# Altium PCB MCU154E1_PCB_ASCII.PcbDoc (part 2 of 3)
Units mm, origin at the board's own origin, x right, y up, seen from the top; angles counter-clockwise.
Board outline 105 x 85 mm, 2 copper layers (Top Layer, Bottom Layer), stack 1.6 mm thick; 179 components, 92 nets, 411 pads, 187 vias.

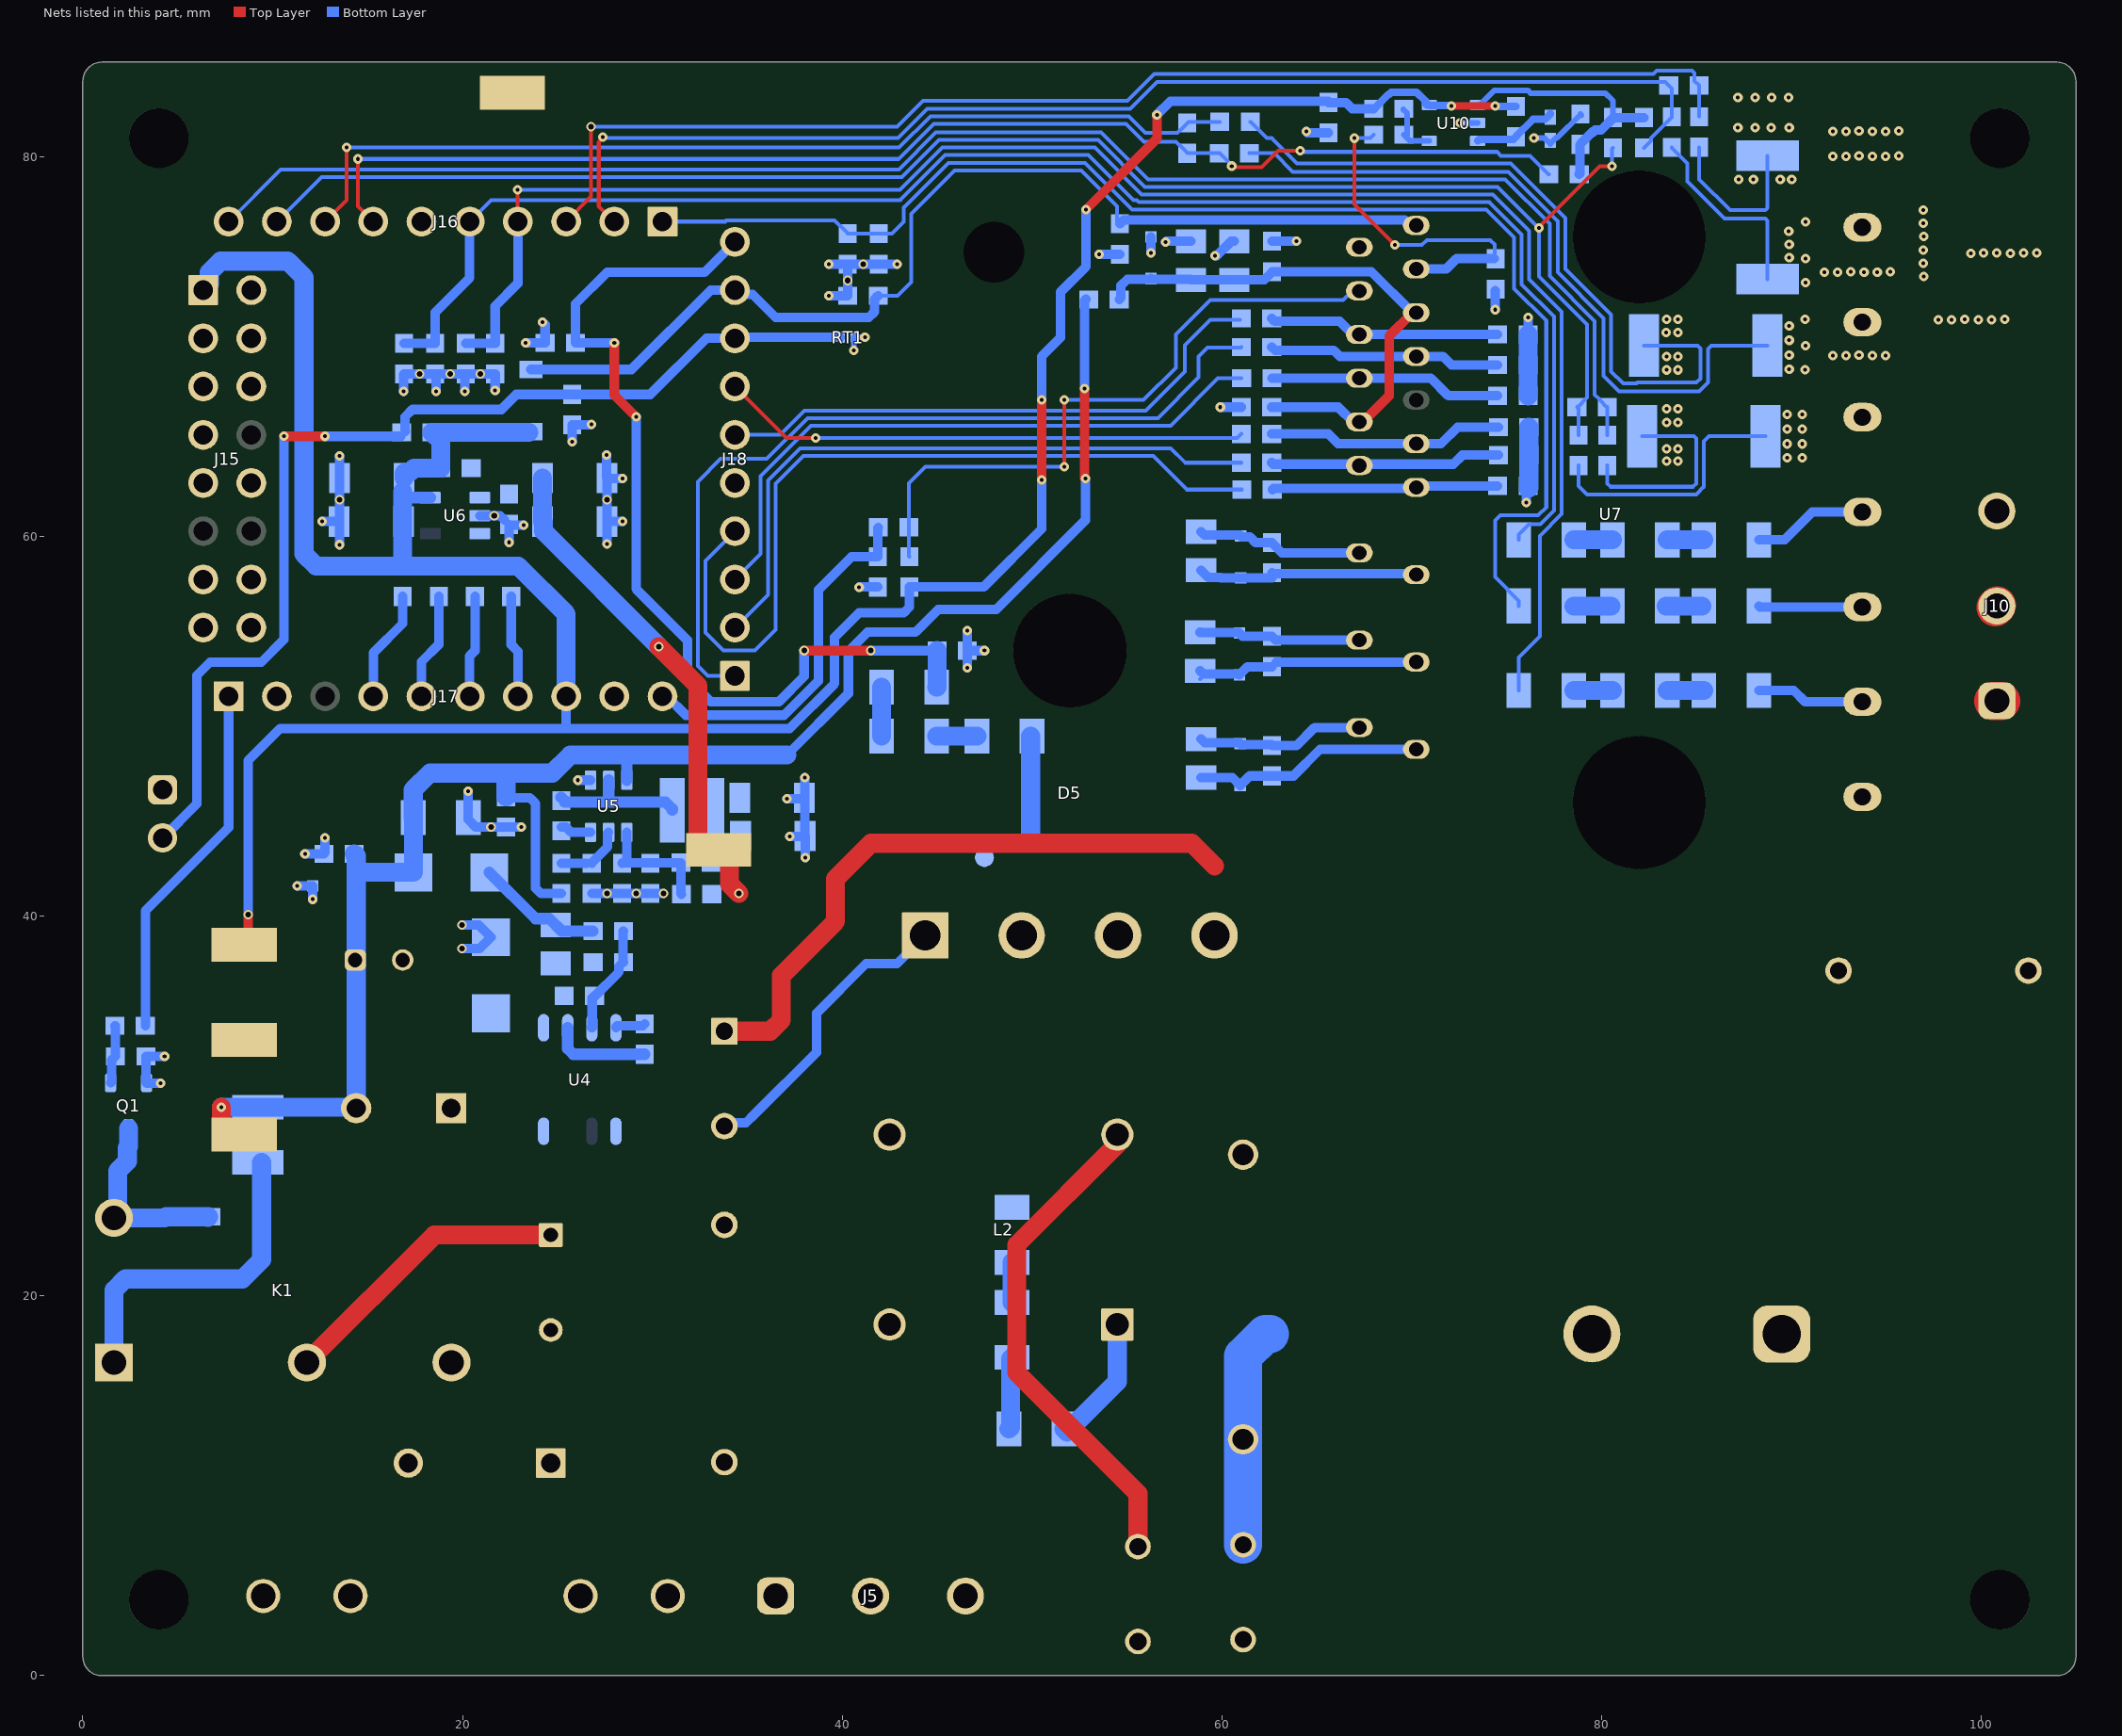
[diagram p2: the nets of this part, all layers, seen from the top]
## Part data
C19 C31 C54 C78: library part CMP-0007402-3, "CAP, CERM, 1000 pF, 25 V, +/- 10%, X7R, 0603"
C32 C57 C60 C62 C72: library part CMP-0008310-1, "CAP, CERM, 10 uF, 35 V, +/- 10%, X5R, 0805"
C33 C40: library part CMP-0067532-1, "CAP, CERM, 2200 pF, X1 250 VAC/Y2 250 VAC, +/- 20%, E, 8x5mm"
C34: library part CMP-0012313-1, "CAP, Film, 0.47 uF, 275 V, +/- 10%, TH"
C35: library part CMP-0007193-4, "CAP, CERM, 20 pF, 50 V, +/- 5%, C0G/NP0, 0603"
C36 C43 C45 C53 C58 C61 C63 C74 C75 C76 C84: library part CMP-0007144-4, "CAP, CERM, 0.1 uF, 50 V, +/- 10%, X7R, 0603"
C37: library part CMP-0008227-2, "CAP, CERM, 0.33 uF, 50 V, +/- 10%, X7R, 0805"
C38: library part CMP-0084882-1, "CAP, AL, 680 µF, 450 V, +/- 20%, TH"
C39: library part CMP-0012314-3, "CAP, Film, 0.1 uF, 275 V, +/- 10%, TH"
C41: library part CMP-0080807-1, "CAP, AL, 100 µF, 35 V, +/- 20%, TH"
C42: library part CMP-0096475-1, "10 µF 400 V Aluminum Electrolytic Capacitors Radial, Can 10000 Hrs @ 105°C"
C44: library part CMP-0081637-1, "CAP, CERM, 10 µF, 35 V,+/- 10%, X5R, 1206"
C46 C47 C49 C50 C51 C52: library part CMP-0008965-2, "CAP, CERM, 10 uF, 25 V, +/- 10%, X7R, 1206"
C48 C79: library part CMP-0007171-4, "CAP, CERM, 100 pF, 50 V, +/- 5%, C0G/NP0, 0603"
C56 C70 C71 C73: library part CMP-0007457-2, "CAP, CERM, 0.047 uF, 50 V, +/- 10%, X7R, 0603"
C59: library part CMP-0012508-3, "CAP, Film, 0.47 uF, 450 V, +/- 10%, TH"
C64 C65 C66 C67 C68 C69: library part CMP-0007442-5, "CAP, CERM, 220 pF, 50 V, +/- 10%, X7R, 0603"
C77 C83: library part CMP-0007402-1, "CAP, CERM, 1000 pF, 25 V, +/- 10%, X7R, 0603"
D3 D12: library part CMP-0028457-2, "Diode, Schottky, 30 V, 0.2 A, SOD-123"
D4 D7: library part CMP-0076882-1, "Diode, Ultrafast, 1000 V, 1 A, SMA"
D5: library part CMP-0096899-4, "Bridge Rectifier Single Phase Standard 600 V Through Hole GBU"
D6 D8 D9 D10 D11: library part CMP-0005835-4, "Diode, Zener, 18 V, 200 mW, SOD-323"
F1: library part CMP-0097018-1, "Fuse Miniature Slow Blow Acting 8A 250V Holder Cartridge 5 X 20mm Ceramic Bulk"
J5 J10: library part CMP-1502-03325-2
J14: library part CMP-0054970-1, "Header, 2.54mm, 2x1, Tin, TH"
J15: library part CMP-0123024-2, "Connector Header Through Hole 16 position 0.100\" (2.54mm)"
J16 J17 J18: library part CMP-0123044-2, "Conn Unshrouded Header HDR 10 POS 2.54mm Solder ST Top Entry Thru-Hole Bag"
K1: library part CMP-0096783-1, "Electromechanical Relay SPST-NO 5(NO)/3(NC)ADC/10(NO)/3(NC)AAC 12VDC 720Ohm Through Hole"
L2: library part CMP-0013082-2, "Coupled inductor, 7 mH, 7 A, 0.02 ohm, TH"
L3: library part CMP-0064862-2, "Inductor, Shielded Drum Core, Metal Composite, 1.8 mH, 0.35 A, 2.7 ohm, TH"
L4: library part CMP-0064362-1, "Inductor, Shielded, Powdered Iron, 6.8 uH, 1.1 A, 0.287 ohm, AEC-Q200 Grade 1, SMD"
LBL1: library part CMP-0003625-1, "Thermal Transfer Printable Labels, 0.650\" W x 0.200\" H - 10,000 per roll"
Logo1: library part CMP-0074844-1
Logo2: library part CMP-0074838-1, "Texas Instrument Corporate Signature"
Logo3: library part CMP-0074847-1, "FCC_disclaimer"
Logo4: library part CMP-0074769-1
LOGO5 LOGO7: library part CMP-0074837-1, "IEC 61010-1 Hot Surface Warning"
LOGO6 LOGO8: library part CMP-0074835-1, "IEC 61010-1 High Voltage Warning"
MP1 MP2 MP3 MP4: library part CMP-0087151-1
Q1: library part CMP-0000775-2, "MOSFET, N-CH, 60 V, 0.36 A, SOT-23"
R8 R55 R85 R88 R97 R98: library part CMP-0022908-4, "RES, 20.0, 1%, 0.1 W, 0603"
R36 R77: library part CMP-0022895-5, "RES, 1.00 k, 1%, 0.1 W, 0603"
R37: library part CMP-0082820-1, "RES, 180, 1%, 0.5 W, 1210"
R38 R43 R78 R100 R101 R102 R103: library part CMP-0022746-5, "RES, 10.0 k, 1%, 0.1 W, 0603"
R39: library part CMP-0096764-1, "PTC Thermistor 70 Ohms Disc, 13mm Dia x 7.5mm W"
R40 R52: library part CMP-0022786-4, "RES, 133 k, 1%, 0.1 W, 0603"
R41 R44 R45: library part CMP-0017836-1, "RES, 100 k, 1%, 0.25 W, 1206"
R42: library part CMP-0097027-1, "3 kA Varistor 1 Circuit Through Hole Disc 13.2mm"
R46 R56 R107 R109: library part CMP-0022906-5, "RES, 20.0 k, 1%, 0.1 W, 0603"
R47 R48 R54 R62 R63 R64 R67 R68 R69 R70 R71 R72: library part CMP-0018207-2, "RES, 332 k, 1%, 0.25 W, 1206"
R49: library part CMP-0022898-4, "RES, 1.50 M, 1%, 0.1 W, 0603"
R50: library part CMP-0022735-5, "RES, 100 k, 1%, 0.1 W, 0603"
R51 R73: library part CMP-0025885-5, "RES, 0, 5%, 0.1 W, 0603"
R53: library part CMP-0022791-5, "RES, 13.7 k, 1%, 0.1 W, 0603"
R57 R74 R75 R76: library part CMP-0023308-5, "RES, 8.20 k, 1%, 0.1 W, 0603"
R58 R59 R60 R61 R65 R66 R79 R106: library part CMP-0022736-4, "RES, 100, 1%, 0.1 W, 0603"
R80 R81 R82: library part CMP-0015791-2, "RES, 0.05, 1%, 2 W, 2512"
R83 R87 R104 R105: library part CMP-0023198-5, "RES, 5.10 k, 1%, 0.1 W, 0603"
R108: library part CMP-0026685-1, "RES, 2.40 k, 1%, 0.1 W, AEC-Q200 Grade 0, 0402"
RT1: library part CMP-0084566-1, "Thermistor, DEC0002A (X1SON-2)"
TP6 TP7 TP8 TP9 TP11: library part CMP-0055152-2, "Test Point, Miniature, SMT"
TPDCBUS: library part CMP-0003825-1, "1mm Test Point, SMT"
U4: library part CMP-0074092-1, "700-V Lowest Quiescent Current Off-Line Switcher, D0007A (SOIC-7)"
U5: library part CMP-0073969-3, "4.5V to 28V Input, 2A Output, EMI Friendly Synchronous Step-Down Converter, DDC0006A (SOT-23-THIN-6)"
U6: library part CMP-0090171-1, "300-mA low-dropout (LDO) regulator with foldback current limit 5-SOT-23 -40 to 125"
U7: library part CMP-0033830-3, "RC-IGBT inverter bridge for three phase DC-to-AC power conversion"
U10: library part CMP-0075716-1, "GENERAL-PURPOSE LOW-VOLTAGE COMPARATOR, DBV0005A (SOT-23-5)"
XF1 XF2: library part CMP-0003676-1, "Fuse Holder, 10A, TH"

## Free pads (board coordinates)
  round 0 hole 3.2 unplated: 2(48,75)

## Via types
v1: diameter 0.5, hole 0.2, Top Layer to Bottom Layer, tented both sides, 167 vias
v2: diameter 0.5, hole 0.3, Top Layer to Bottom Layer, tented both sides, 20 vias

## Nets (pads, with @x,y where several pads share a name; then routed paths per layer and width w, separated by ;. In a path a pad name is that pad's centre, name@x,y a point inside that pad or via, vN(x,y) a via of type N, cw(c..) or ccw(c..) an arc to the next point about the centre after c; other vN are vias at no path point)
3.3V: C46.1 C47.1 C84.1 D12.1 J15.1 J17.8 R51.2 R77.2 R78.1 R100.1 R101.1 R102.1 R103.1 R107.2 R109.1 TP8.1 U6.5 U10.5 | length 160.5
  Top Layer w0.4: v1(72.11,82.69) v1(74.398,82.69)
  Top Layer w0.5: TP8.1@8.5,38.5 8.7,38.7 v2(8.7,40.1) ; v1(50.517,62.985) v1(50.517,67.2) ; v1(52.843,77.236) 56.601,80.993 56.601,82.209 v1(56.583,82.228)
  Bottom Layer w0.4: R109.1@68,82.542 68.025,82.542 68.804,83.322 68.838,83.322 68.934,83.417 70.265,83.417 70.729,82.954 70.729,82.823 70.804,82.748 U10.5@70.929,82.748 70.968,82.709 72.091,82.709 v1(72.11,82.69) ; v1(74.398,82.69) 74.411,82.677 75.493,82.677 R107.2@75.505,82.664
  Bottom Layer w0.5: v2(8.7,40.1) 8.7,48.2 10.4,49.9 25.545,49.9 ; J17.8@25.46,51.6 25.46,49.985 25.545,49.9 ; v1(50.517,62.985) 50.517,60.417 47.45,57.35 R78.1@43.545,57.35 43.545,56.293 43.252,56 40.9,56 39.607,54.707 39.607,52.268 37.239,49.9 25.545,49.9 ; v1(50.517,67.2) 50.517,69.5 51.5,70.483 51.5,72.878 52.843,74.221 v1(52.843,77.236) ; v1(56.583,82.228) 57.286,82.931 C84.1@65.619,82.931 ; C84.1@65.63,82.87 66.552,82.87 66.879,82.542 R109.1@68,82.542
  Bottom Layer w0.6: C47.1@16.844,62.366 17.149,62.06 U6.5@18.309,62.06
  Bottom Layer w1: J15.1@6.34,72.99 6.665,73.315 6.665,73.929 7.251,74.515 10.799,74.515 11.65,73.664 11.65,59.089 12.286,58.454 R100.1@16.844,58.454 ; C47.1@16.844,62.366 R100.1@16.844,58.454 ; C47.1@16.924,63.089 16.924,63.339 16.974,63.389 17.224,63.389 17.447,63.612 R51.2@18.859,63.612 18.859,65.026 18.4,65.485 R77.2@18.4,65.5 D12.1@23.5,65.5 ; J17.8@25.46,51.6 25.46,55.925 22.931,58.454 R102.1@20.659,58.454 R101.1@18.751,58.454 R100.1@16.844,58.454
5V: C48.1 C49.1 C50.1 C51.1 C52.1 C53.1 L4.2 R50.2 R51.1 TP7.1 U6.1 U6.3 | length 26.7
  Top Layer w1: v2(30.351,54.206) 32.4,52.156 32.4,43.889 32.789,43.5 TP7.1@33.5,43.5 33.683,43.5 34.072,43.111 34.072,41.697 v2(34.569,41.2)
  Bottom Layer w1: C51.1@24.221,63.089 C52.1@24.221,60.8 24.271,60.75 24.271,60.286 v2(30.351,54.206)
15V: C41.1 C44.1 C45.1 D4.2 D6.1 L3.2 R37.1 R46.2 R49.2 R73.1 TP6.1 U5.3 | length 94
  Top Layer w0.5: v1(52.774,67.811) 52.774,63.102 v1(52.816,63.06)
  Top Layer w1: v1(7.288,29.939) 7.288,28.712 TP6.1@7.5,28.5
  Bottom Layer w0.5: C45.1@22.295,46.3 22.345,46.25 23.556,46.25 23.849,45.957 23.849,41.493 24.142,41.2 R49.2@25.2,41.2 ; 37.095,48.5 40.33,51.735 40.33,53.963 41.348,54.98 43.875,54.98 45.067,56.173 48.12,56.173 52.816,60.868 v1(52.816,63.06) ; v1(52.774,67.811) 52.774,72.442 R73.1@52.837,72.506
  Bottom Layer w0.6: U5.3@28.65,47.175 28.65,48.5
  Bottom Layer w1: v1(7.288,29.939) 9.21,29.939 R37.1@9.219,29.948 14.352,29.948 L3.2@14.4,29.9 14.4,42.317 ; R46.2@14.3,43.3 14.4,43.2 14.4,42.317 ; C45.1@22.295,46.3 22.295,47.55 ; 37.095,48.5 28.65,48.5 25.681,48.5 24.73,47.55 22.295,47.55 ; 14.4,42.317 D4.2@17.417,42.317 17.417,45.189 C44.1@17.406,45.2 17.406,46.67 18.286,47.55 22.295,47.55
EGND: C33.2 C40.1 J5.3
GND: C32.2 C38.2 C41.2 C42.1 C44.2 C45.2 C46.2 C47.2 C49.2 C50.2 C51.2 C52.2 C53.2 C56.2 C59.2 C64.1 C65.1 C66.1 C67.1 C68.1 C69.1 C70.2 C71.2 C72.2 C73.2 C74.2 C75.2 C76.2 C77.2 C78.1 C79.2 C83.2 C84.2 D5.4 D6.2 D7.2 D11.2 J14.1 J15.2 J15.7 J16.6 J17.9 J18.5 Q1.2 R38.1 R46.1 R52.1 R53.1 R56.1 R57.1 R74.1 R75.1 R76.1 R80.1 R81.1 R82.1 R83.1 R88.1 R97.1 R98.1 R108.1 RT1.1 TP9.1 TP11.1 U5.1 U6.2 U7.19 U10.2 | length 176.3
  Top Layer w1: TP11.1@22.419,83.59 TP11.1@22.626,83.382 ; C42.1@33.8,33.95 36.214,33.95 36.8,34.536 36.8,36.883 39.655,39.738 39.655,41.986 41.519,43.85 58.431,43.85 59.62,42.661
  Top Layer w2: D5.4@59.534,39.086 D5.4@59.62,39
  Bottom Layer w0.2: R88.1@61.502,81.859 61.527,81.859 62.386,81 62.635,81 63.964,79.67 75.22,79.67 78.1,76.79 78.1,74.115 80.518,71.697 80.518,68.708 81.158,68.068 81.841,68.068 81.891,68.118 85.003,68.118 85.216,68.331 85.216,69.924 85.072,70.068 R81.1@82.25,70.068 ; R97.1@80.315,63.75 80.315,62.797 80.48,62.633 84.825,62.633 84.997,62.805 84.997,65.18 84.88,65.297 R82.1@82.147,65.297 ; R98.1@85.152,80.518 85.152,78.832 86.782,77.203 88.637,77.203 88.754,77.32 R80.1@88.754,80.073
  Bottom Layer w0.3: v1(40.625,69.809) RT1.1@40.625,70.5 v1(41.2,70.5) ; v1(72.554,81.798) U10.2@73.479,81.798 ; C83.2@74.35,73.044 C83.2@74.4,72.994 ; v1(76.453,81) 77.006,81 77.32,80.687 77.32,80.712 77.645,81.037 77.693,81.037 78.897,82.241 C79.2@78.897,82.266 C79.2@78.958,82.204
  Bottom Layer w0.5: v1(4.1,31.2) 3.383,31.2 Q1.2@3.356,31.227 3.318,31.265 R38.1@3.318,32.629 v1(4.306,32.629) ; v1(11.3,41.606) D6.2@12.1,41.606 v1(12.1,40.9) ; v1(11.7,43.3) R46.1@12.7,43.3 12.76,43.36 v1(12.76,44.13) ; v1(12.6,60.8) C46.2@13.5,60.8 13.524,60.776 v1(13.524,59.579) ; v1(13.512,64.25) 13.512,63.1 C47.2@13.524,63.089 v2(13.524,61.956) C46.2@13.524,60.824 ; v1(16.9,67.648) 16.9,68.555 R76.1@16.923,68.578 C71.2@18.559,68.578 ; v1(18.61,67.648) 18.61,68.528 C71.2@18.559,68.578 ; v2(19.968,38.297) 20.897,38.297 D7.2@21.5,38.9 20.853,39.547 v2(19.968,39.547) ; v1(20.112,67.648) 20.112,68.525 R74.1@20.166,68.578 ; v1(20.306,46.597) C44.2@20.306,45.2 20.306,45.1 20.706,44.7 v2(21.501,44.7) C45.2@22.295,44.7 v1(23.105,44.7) ; U6.2@20.909,61.11 v2(21.674,61.11) 21.987,61.11 C53.2@22.202,60.895 ; v1(21.721,67.702) C73.2@21.721,68.578 R74.1@20.166,68.578 ; v1(22.452,59.705) C53.2@22.452,60.645 22.497,60.6 v1(23.221,60.6) ; v1(23.334,70.209) C56.2@24.352,70.209 24.352,71.169 v1(24.221,71.3) ; v1(25.781,65) C76.2@25.781,65.895 v1@26.781,65.895 ; v1(26.081,47.175) U5.1@26.75,47.175 ; R52.1@26.811,41.2 R53.1@28.401,41.2 v2(29.146,41.2) R56.1@29.891,41.2 29.905,41.214 v2(30.587,41.214) ; v1(27.6,64.3) 27.6,63.109 C51.2@27.621,63.089 ; v1(27.606,59.627) 27.606,60.785 C52.2@27.621,60.8 ; v1(28.432,60.8) C52.2@27.621,60.8 ; v1(28.432,63.06) 27.649,63.06 C51.2@27.621,63.089 ; v1(37.1,46.2) 37.959,46.2 C50.2@38.009,46.25 ; v1(37.239,44.212) 38.03,44.212 C49.2@38.049,44.23 ; v1(38.029,47.31) 38.029,46.27 C50.2@38.009,46.25 ; v1(38.067,43.1) 38.067,44.212 C49.2@38.049,44.23 ; v1(39.3,72.7) C78.1@40.3,72.7 R75.1@40.3,74.363 ; v1(39.3,74.363) R75.1@40.3,74.363 ; v1(40.9,57.333) 40.917,57.35 C77.2@41.883,57.35 ; v1(42.9,74.363) C70.2@41.933,74.363 R75.1@40.3,74.363 ; v1(46.6,53.1) R57.1@46.6,54 ; v1(46.6,55.052) R57.1@46.6,54 ; v1(47.5,54) R57.1@46.6,54 ; v1(53.543,74.882) R83.1@54.625,74.882 ; D11.2@56.274,75.799 56.274,74.963 v1(56.279,74.958) ; v1(57.049,75.512) 57.101,75.564 C72.2@58.386,75.564 ; v1(59.646,74.799) 59.733,74.799 60.497,75.564 C32.2@60.662,75.564 ; v1(59.929,66.825) C74.2@61.035,66.825 ; C75.2@62.646,75.564 v1(63.945,75.564) ; v1(64.459,81.342) 64.52,81.28 C84.2@65.619,81.28 ; v1(74.4,71.96) C83.2@74.4,72.965 ; v1(76.053,61.791) 76.053,62.454 C64.1@76.14,62.541 ; C69.1@76.14,71.049 v1(76.14,71.558) ; C71.2@18.559,68.578 R74.1@20.166,68.578 ; C52.2@27.621,60.8 C51.2@27.621,63.089 ; C50.2@38.009,46.25 38.029,46.23 38.029,44.25 C49.2@38.049,44.23
  Bottom Layer w1: C42.1@33.8,33.95 C42.1@34,34.15 ; C64.1@76.14,62.541 76.178,62.579 C66.1@76.178,64.297 ; C65.1@76.14,67.424 C67.1@76.14,69.04 C69.1@76.14,70.65 ; C66.1@76.178,64.322 C68.1@76.178,65.772
  other v1: 83.437,63.99 84.036,63.99 83.437,64.635 84.036,64.635 26.8,65.914 83.437,66.018 84.036,66.018 83.437,66.731 84.036,66.731 83.437,68.787 84.036,68.787 83.437,69.5 84.036,69.483 84.036,70.749 83.418,70.757 83.437,71.462 84.036,71.462 87.237,78.823 88.015,78.823 89.429,78.823 90.027,78.823 87.196,81.554 88.107,81.554 88.953,81.554 89.9,81.554 87.196,83.13 88.107,83.13 88.966,83.13 89.865,83.13
  other v2: 27.606,41.2 27.621,61.944 17.741,68.578 19.362,68.578 20.944,68.578 40.3,73.5 41.116,74.363
IPM_15V: C32.1 C72.1 C74.1 C75.1 D11.1 R73.2 U7.11 U7.16 | length 29.7
  Top Layer w0.5: U7.11@67.25,66.05 67.45,66.05 68.816,67.416 68.816,70.566 70.05,71.8 U7.16@70.25,71.8
  Bottom Layer w0.5: R73.2@54.6,72.5 54.687,72.587 54.687,73.225 55.028,73.566 D11.1@56.274,73.566 ; D11.1@56.274,73.599 56.308,73.566 58.352,73.566 C72.1@58.386,73.532 C32.1@60.662,73.532 62.239,73.532 62.646,73.939 C75.1@62.646,73.964 67.886,73.964 70.05,71.8 U7.16@70.25,71.8 ; C74.1@62.635,66.825 66.14,66.825 66.915,66.05 U7.11@67.25,66.05
IPM_CIN: C83.1 R106.2 U7.18 | length 18.3
  Top Layer w0.2: v1(66.991,80.993) 66.991,77.507 v1(69.131,75.367)
  Bottom Layer w0.2: v1(66.991,80.993) 66.922,80.993 66.915,81 67.827,81 R106.2@68,81.173 ; v1(69.131,75.367) 70.549,75.367 70.809,75.627 74.147,75.627 74.38,75.394 74.38,74.674 C83.1@74.35,74.644
  Bottom Layer w0.5: U7.18@70.25,74.1 71.821,74.1 72.365,74.644 C83.1@74.35,74.644
IPM_FAULT: C77.1 J17.10 R79.1 | length 19.6
  Bottom Layer w0.5: J17.10@30.54,51.6 30.767,51.6 31.767,50.6 36.949,50.6 38.755,52.406 38.755,57.205 40.5,58.95 C77.1@41.883,58.95 41.883,60.465 R79.1@41.914,60.496
IPM_PWM_UH: C64.2 R58.2 U7.8 | length 12
  Bottom Layer w0.5: R58.2@62.662,62.484 62.721,62.542 70.192,62.542 70.329,62.679 C64.2@74.54,62.679
IPM_PWM_UL: C65.2 R59.2 U7.13 | length 12.3
  Bottom Layer w0.5: R59.2@62.644,68.349 U7.13@67.25,68.35 71.017,68.35 71.942,67.424 C65.2@74.54,67.424
IPM_PWM_VH: C66.2 R60.2 U7.9 | length 12.2
  Bottom Layer w0.5: R60.2@62.635,63.898 62.709,63.824 67.176,63.824 U7.9@67.25,63.75 ; U7.9@67.25,63.824 72.204,63.824 72.678,64.297 C66.2@74.578,64.297
IPM_PWM_VL: C67.2 R61.2 U7.14 | length 12.3
  Bottom Layer w0.5: R61.2@62.635,69.992 62.818,69.809 65.908,69.809 66.217,69.5 U7.14@70.25,69.5 71.65,69.5 72.11,69.04 C67.2@74.54,69.04
IPM_PWM_WH: C68.2 R65.2 U7.10 | length 12.5
  Bottom Layer w0.5: R65.2@62.635,65.414 65.619,65.414 66.133,64.9 U7.10@70.25,64.9 71.56,64.9 72.432,65.772 C68.2@74.578,65.772
IPM_PWM_WL: C69.2 R66.2 U7.15 | length 12.3
  Bottom Layer w0.5: R66.2@62.635,71.502 62.79,71.347 66.217,71.347 66.915,70.65 U7.15@67.25,70.65 C69.2@74.54,70.65
IPM_TEMP_AD: C78.2 D12.2 J18.9 R83.2 U7.20 | length 56.5
  Bottom Layer w0.2: C78.2@41.9,72.7 42.935,72.7 43.644,73.409 43.644,77.018 45.926,79.3 52.6,79.3 54.491,77.409 54.491,76.616 R83.2@54.625,76.482
  Bottom Layer w0.5: D12.2@23.61,68.808 28.898,68.808 33.08,72.99 J18.9@34.36,72.99 34.58,72.77 35.279,72.77 36.5,71.549 41.407,71.549 41.7,71.842 41.7,72.5 C78.2@41.9,72.7 ; R83.2@54.625,76.482 54.822,76.679 69.636,76.679 69.915,76.4 U7.20@70.25,76.4
IU_N: C54.1 J16.10 R97.2 | length 85.9
  Bottom Layer w0.2: J16.10@7.68,76.6 10.43,79.35 42.987,79.35 44.937,81.3 53.648,81.3 56.119,78.829 74.93,78.829 77.275,76.484 77.275,73.727 79.654,71.348 79.654,67.486 79.915,67.225 79.915,67.2 80.29,66.825 C54.1@80.315,66.825 R97.2@80.315,65.35
IU_P: C54.2 J16.9 R85.2 R87.1 | length 88.6
  Top Layer w0.2: v1(76.725,76.256) 76.725,76.315 79.919,79.509 v1(80.566,79.509)
  Bottom Layer w0.2: J16.9@10.22,76.6 12.57,78.95 43.153,78.95 45.103,80.9 53.481,80.9 55.952,78.429 74.522,78.429 76.694,76.256 v1(76.725,76.256) ; v1@76.71,76.241 76.725,76.226 76.725,73.712 79.254,71.182 79.254,67.339 78.74,66.825 C54.2@78.715,66.825 78.807,66.732 R85.2@78.807,65.35 ; v1(80.566,79.509) 80.566,80.429 R87.1@80.618,80.48
IV_N: C31.1 J16.8 R88.2 | length 51.7
  Top Layer w0.2: J16.8@12.76,76.6 13.9,77.74 v1(13.9,80.5)
  Bottom Layer w0.2: v1(13.9,80.5) 43.006,80.5 44.66,82.154 55.111,82.154 55.978,81.286 57.669,81.286 57.783,81.4 57.808,81.4 58.267,81.859 R88.2@59.902,81.859
IV_P: C31.2 J16.7 R55.2 R104.1 | length 69
  Top Layer w0.2: v1(14.5,79.9) 14.5,77.4 J16.7@15.3,76.6 ; v1(60.526,79.526) 60.579,79.474 62.106,79.474 62.958,80.326 v1(64.134,80.326)
  Bottom Layer w0.2: v1(14.5,79.9) 42.972,79.9 44.825,81.754 54.945,81.754 55.893,80.806 57.577,80.806 57.783,80.6 57.808,80.6 58.183,80.225 C31.2@58.183,80.2 R55.2@59.862,80.2 59.887,80.2 60.526,79.56 v1(60.526,79.526) ; v1(64.134,80.326) 64.188,80.273 74.511,80.273 74.713,80.07 76.236,80.07 77.208,79.098 R104.1@77.233,79.098
IW_N: C19.1 J16.3 R98.2 | length 67.3
  Top Layer w0.2: J16.3@25.46,76.6 26.781,77.921 v2(26.781,81.6)
  Bottom Layer w0.2: v2(26.781,81.6) 42.9,81.6 44.254,82.954 55.02,82.954 56.438,84.372 82.752,84.372 82.928,84.548 84.78,84.548 84.91,84.417 84.91,84.015 C19.1@85.152,83.773 R98.2@85.152,82.143
IW_P: C19.2 J16.2 R8.2 R105.1 | length 66.3
  Top Layer w0.2: v1(27.4,81.05) 27.4,81.002 27.181,80.783 27.181,77.419 J16.2@28,76.6
  Bottom Layer w0.2: v1(27.4,81.05) 27.45,81 42.94,81 44.494,82.554 55.186,82.554 56.596,83.964 83.361,83.964 83.715,83.61 R8.2@83.715,82.115 83.715,82.09 82.625,81 82.625,80.855 R105.1@82.25,80.48
LINE: J5.1 XF1.1 XF1.2
MCU_TCK: J15.4
MCU_TDI: J15.5
MCU_TDO: J15.6
MCU_TMS: J15.3
MISC_IO: J17.2
MOTOR_TEMP_AD: C76.1 J14.2 J18.8 R77.1 RT1.2 | length 57
  Top Layer w0.5: v1(10.6,65.3) 10.612,65.288 v1(12.76,65.288)
  Bottom Layer w0.5: J14.2@4.2,44.13 6,45.93 6,52.7 6.695,53.395 9.4,53.395 10.6,54.595 v1(10.6,65.3) ; v1(12.76,65.288) R77.1@16.755,65.288 ; R77.1@17.005,65.538 16.974,65.57 16.974,66.313 17.361,66.7 22.045,66.7 22.84,67.495 C76.1@25.781,67.495 29.891,67.495 32.846,70.45 J18.8@34.36,70.45 34.41,70.5 RT1.2@39.9,70.5
MOTOR_U: J10.1 R62.2 U7.26 | length 6.1
  Top Layer w2: J10.1@100.645,51.351 J10.1@101.065,51.351
  Bottom Layer w0.5: R62.2@88.297,51.9 90.141,51.9 90.741,51.3 U7.26@93.75,51.3
MOTOR_V: J10.2 R63.2 U7.25 | length 5.6
  Top Layer w2: J10.2@100.752,56.287 J10.2@100.852,56.387
  Bottom Layer w0.5: R63.2@88.297,56.351 88.348,56.3 U7.25@93.75,56.3
MOTOR_W: J10.3 R64.2 U7.24 | length 6.1
  Bottom Layer w0.5: R64.2@88.297,59.835 89.654,59.835 91.118,61.3 U7.24@93.75,61.3
NetC33_1: C33.1 C39.1 D5.2 L2.2 R41.2 | length 26
  Top Layer w1: L2.2@54.5,28 49.2,22.7 49.2,15.973 55.588,9.585 C33.1@55.588,6.8
NetC34_1: C34.1 K1.3 L2.3 R39.2
NetC35_1: C35.1 R40.1 R43.2 U4.3 | length 5.8
  Bottom Layer w0.5: U4.3@26.796,34.15 U4.3@26.815,34.131 26.834,34.15 26.834,35.687 C35.1@26.956,35.81 26.981,35.81 28.23,37.058 28.23,37.358 28.455,37.583 R43.2@28.457,37.583 ; R43.2@28.48,37.583 28.469,37.595 28.469,39.211 R40.1@28.48,39.222
NetC35_2: C35.2 C36.2 C37.2 D7.1 L3.1 R43.1 U4.1 U4.2 | length 5.3
  Bottom Layer w0.6: U4.2@25.545,34.131 25.545,33.029 25.838,32.737 C36.2@29.6,32.737
NetC36_1: C36.1 U4.4 | length 1.6
  Bottom Layer w0.5: U4.4@28.085,34.131 28.085,34.188 28.131,34.234 29.497,34.234 C36.1@29.6,34.337
NetC37_1: C37.1 D4.1 R40.2 | length 6.7
  Bottom Layer w0.6: D4.1@21.417,42.317 23.852,39.882 24.572,39.882 25.232,39.222 R40.2@26.88,39.222
NetC39_2: C39.2 C40.2 D5.3 L2.1 R45.1 | length 18.8
  Bottom Layer w1: R45.1@51.689,13 51.851,12.838 54.5,15.487 L2.1@54.5,18.5
  Bottom Layer w2: C40.2@61.126,6.9 C39.2@61.126,12.45 61.126,16.828 62.297,18 62.55,18
NetC43_1: C43.1 U5.6 | length 1.7
  Bottom Layer w0.5: C43.1@25.198,44.7 25.46,44.7 25.735,44.425 U5.6@26.75,44.425
NetC43_2: C43.2 L4.1 U5.2 | length 7.4
  Bottom Layer w0.6: C43.2@25.198,46.275 25.373,46.1 25.373,46.015 25.375,46.013 27.7,46.013 ; U5.2@27.7,47.175 27.7,46.013 ; L4.1@31.05,45.595 31.05,45.663 30.7,46.013 27.7,46.013
NetC48_2: C48.2 R50.1 R53.2 R56.2 U5.4 | length 6.1
  Bottom Layer w0.5: R53.2@28.401,42.8 28.432,42.831 C48.2@31.507,42.831 31.507,41.199 R50.1@31.537,41.169 ; R53.2@28.65,43.074 U5.4@28.65,44.425
NetC57_1: C57.1 C58.1 D8.2 U7.2 | length 12.3
  Bottom Layer w0.5: C57.1@58.913,47.31 60.564,47.31 D8.2@60.974,46.9 61.474,47.4 C58.1@62.644,47.4 63.781,47.4 65.181,48.8 U7.2@70.25,48.8
NetC57_2: C57.2 C58.2 D8.1 U7.3 | length 8.9
  Bottom Layer w0.5: C57.2@58.913,49.342 59.105,49.15 60.924,49.15 D8.1@60.974,49.1 61.024,49.05 62.619,49.05 62.669,49 63.945,49 64.895,49.95 U7.3@67.25,49.95
NetC60_1: C60.1 C61.1 D9.2 U7.4 | length 11.5
  Bottom Layer w0.2: C60.1@58.864,52.502 C60.1@58.903,52.541
  Bottom Layer w0.5: C60.1@58.864,52.936 59.027,52.773 60.876,52.773 D9.2@60.926,52.723 61.355,53.152 C61.1@62.644,53.152 ; C61.1@62.869,53.4 U7.4@70.25,53.4
NetC60_2: C60.2 C61.2 D9.1 U7.5 | length 8.6
  Bottom Layer w0.5: C60.2@58.864,54.968 58.887,54.945 60.903,54.945 D9.1@60.926,54.923 61.097,54.752 C61.2@62.644,54.752 62.845,54.55 U7.5@67.25,54.55
NetC62_1: C62.1 C63.1 D10.2 U7.6 | length 11.5
  Bottom Layer w0.5: C62.1@58.913,58.233 59.298,57.848 59.937,57.848 59.949,57.835 D10.2@60.999,57.835 C63.1@62.646,57.835 ; C63.1@62.646,58.1 62.696,58.05 70.2,58.05 U7.6@70.25,58
NetC62_2: C62.2 C63.2 D10.1 U7.7 | length 8.8
  Bottom Layer w0.5: C62.2@58.913,60.265 59.092,60.085 60.949,60.085 D10.1@60.999,60.035 61.049,59.985 61.488,59.985 61.773,59.7 C63.2@62.646,59.7 62.646,59.675 63.171,59.15 U7.7@67.25,59.15
NetC79_1: C79.1 R87.2 R104.2 R105.2 U10.1 | length 14.1
  Bottom Layer w0.3: U10.1@73.479,82.748 73.604,82.748 74.37,83.514 76.125,83.514 76.267,83.372 80.208,83.372 80.618,82.963 R87.2@80.618,82.08 R87.2@80.618,82.055
  Bottom Layer w0.5: R104.2@78.833,79.098 78.865,79.13 78.865,80.634 C79.1@78.897,80.666 78.897,80.691 79.522,81.316 79.558,81.316 79.672,81.43 79.993,81.43 R87.2@80.618,82.055 ; R87.2@80.618,82.08 R105.2@82.25,82.08
NetD3_1: D3.1 K1.1 R37.2 | length 17.4
  Bottom Layer w1: K1.1@1.64,16.5 1.64,20.314 2.226,20.9 D3.1@6.633,20.9 8.414,20.9 9.419,21.905 R37.2@9.419,27.048
NetD3_2: D3.2 K1.5 Q1.3 | length 10.1
  Bottom Layer w1: Q1.3@2.406,28.827 2.406,27.857 2.347,27.798 2.347,27.097 1.831,26.582 1.831,24.311 K1.5@1.64,24.12 4.306,24.12 4.361,24.175 D3.2@6.633,24.175 D3.2@6.591,24.132
NetK1_2: K1.2 R39.1 R42.2 XF2.1 XF2.2 | length 15.6
  Top Layer w1: K1.2@11.8,16.5 18.513,23.213 R39.1@24.65,23.213
NetQ1_1: Q1.1 R36.2 R38.2 | length 3.1
  Bottom Layer w0.5: Q1.1@1.456,31.227 1.506,31.277 1.506,32.417 R38.2@1.718,32.629 1.704,32.643 1.704,34.229 R36.2@1.691,34.243
NetR8_1: R8.1 R80.2 U7.21 | length 10.3
  Bottom Layer w0.2: R8.1@83.715,80.515 83.715,80.49 84.533,79.672 84.533,78.725 86.492,76.766 88.637,76.766 88.754,76.649 R80.2@88.754,73.573
  other v1: 90.754,73.39 96.988,73.719 91.746,73.94 92.44,73.94 93.846,73.94 94.54,73.94 93.13,73.964 95.23,73.964 96.964,74.409 90.754,74.644 89.9,74.707 99.456,74.934 101.556,74.934 100.146,74.957 100.84,74.957 102.246,74.957 102.94,74.957 96.964,75.103 89.9,75.401 96.988,75.819 89.876,76.091 96.964,76.509 90.754,76.583 96.964,77.203 92.189,80.03 92.883,80.03 94.289,80.03 94.983,80.03 93.573,80.054 95.673,80.054 92.189,81.343 92.883,81.343 94.289,81.343 94.983,81.343 93.573,81.367 95.673,81.367
NetR41_1: R41.1 R44.2 | length 2.1
  Bottom Layer w1: R44.2@48.952,19.663 R41.1@48.952,21.773
NetR44_1: R44.1 R45.2 | length 3.8
  Bottom Layer w1: R45.2@48.789,13 48.87,13.081 48.87,16.682 R44.1@48.952,16.763
NetR47_1: R47.1 R48.2 | length 2.1
  Bottom Layer w1: R48.2@44.985,49.5 R47.1@47.105,49.5
NetR48_1: R48.1 R54.2 | length 2.6
  Bottom Layer w1: R48.1@42.085,49.5 R54.2@42.085,52.073
NetR49_1: R49.1 R52.2 U5.5 | length 3.3
  Bottom Layer w0.5: R49.1@25.2,42.8 R52.2@26.532,42.8 ; R52.2@26.811,42.8 26.811,42.825 27.65,43.664 27.65,44.375 U5.5@27.7,44.425
NetR55_1: R55.1 R81.2 U7.22 | length 37.9
  Bottom Layer w0.2: R55.1@61.462,80.2 62.77,80.2 63.741,79.229 75.096,79.229 77.7,76.625 77.7,73.925 80.118,71.508 80.118,68.484 80.934,67.668 85.152,67.668 85.616,68.131 85.616,69.881 85.803,70.068 R81.2@88.75,70.068
  other v1: 90.733,68.794 89.9,68.832 92.189,69.538 92.883,69.538 94.289,69.538 94.983,69.538 89.9,69.562 93.573,69.562 90.757,70.068 89.9,70.35 89.9,71.102 90.733,71.452 97.76,71.438 98.454,71.438 99.144,71.462 99.86,71.438 100.554,71.438 101.244,71.462
NetR62_1: R62.1 R67.2 | length 1.9
  Bottom Layer w1: R67.2@83.479,51.9 R62.1@85.397,51.9
NetR63_1: R63.1 R68.2 | length 1.9
  Bottom Layer w1: R68.2@83.418,56.351 R63.1@85.304,56.351
NetR64_1: R64.1 R69.2 | length 1.9
  Bottom Layer w1: R69.2@83.479,59.835 R64.1@85.397,59.835
NetR67_1: R67.1 R70.2 | length 2
  Bottom Layer w1: R70.2@78.55,51.9 R67.1@80.579,51.9
NetR68_1: R68.1 R71.2 | length 2
  Bottom Layer w1: R71.2@78.55,56.351 R68.1@80.518,56.351
NetR69_1: R69.1 R72.2 | length 2
  Bottom Layer w1: R72.2@78.55,59.835 R69.1@80.579,59.835
NetR78_2: R78.2 R79.2 U7.17 | length 34.9
  Top Layer w0.2: v1(51.7,63.69) v1(51.7,67.2)
  Bottom Layer w0.2: R78.2@43.545,58.95 43.514,58.981 R79.2@43.514,60.496 43.514,62.81 44.393,63.69 v1(51.7,63.69) ; v1(51.7,67.2) 55.872,67.2 57.577,68.905 57.577,70.655 59.392,72.47 66.399,72.47 66.879,72.95 U7.17@67.25,72.95
NetR82_2: R82.2 R85.1 U7.23 | length 13.8
  Bottom Layer w0.2: R85.1@78.807,63.75 78.807,62.679 79.254,62.233 79.876,62.233 84.997,62.233 85.397,62.633 85.397,65.024 85.67,65.297 R82.2@88.647,65.297
  other v1: 89.797,64.161 90.59,64.161 89.797,64.891 90.59,64.891 89.797,65.679 90.59,65.679 89.797,66.431 90.59,66.431
NetR106_1: R106.1 R109.2 U10.4 | length 2.9
  Bottom Layer w0.3: R109.2@69.564,82.506 69.772,82.298 R106.1@69.772,81.173 ; R106.1@69.6,81.173 69.924,80.848 U10.4@70.929,80.848
NetR107_1: R107.1 R108.2 U10.3 | length 4.5
  Bottom Layer w0.4: U10.3@73.479,80.848 73.554,80.923 75.365,80.923 R107.1@75.505,81.064 75.505,81.089 76.404,81.987 77.045,81.987 77.32,82.262 R108.2@77.32,82.287
NEU: C34.2 J5.2 L2.4 R42.1
PC_RX: J15.9
PC_TX: J15.10
PWM_UH: J18.4 R58.1 | length 44.1
  Bottom Layer w0.2: J18.4@34.36,60.29 32.8,58.73 32.8,54.943 33.743,54 35.397,54 36.5,55.104 36.5,62.8 37.95,64.25 56.393,64.25 58.159,62.484 R58.1@61.062,62.484
PWM_UL: J18.3 R59.1 | length 33.5
  Bottom Layer w0.2: J18.3@34.36,57.75 35.7,59.09 35.7,63.202 38.348,65.85 57.302,65.85 59.801,68.349 R59.1@61.044,68.349
PWM_VH: J18.2 R60.1 | length 34.4
  Bottom Layer w0.2: J18.2@34.36,55.21 36.1,56.95 36.1,61.995 36.1,62.783 36.1,62.966 37.784,64.65 37.967,64.65 38.755,64.65 57.32,64.65 58.073,63.898 R60.1@61.035,63.898
PWM_VL: J18.1 R61.1 | length 44.1
  Bottom Layer w0.2: J18.1@34.36,52.67 32.93,52.67 32.4,53.2 32.4,62.9 33.6,64.1 36.032,64.1 38.182,66.25 56.64,66.25 58.784,68.393 58.784,69.488 59.257,69.962 61.004,69.962 R61.1@61.035,69.992
PWM_WH: J18.7 R65.1 | length 27.9
  Top Layer w0.2: J18.7@34.36,67.91 37.07,65.2 v1(38.6,65.2)
  Bottom Layer w0.2: v1(38.6,65.2) 60.821,65.2 R65.1@61.035,65.414
PWM_WL: J18.6 R66.1 | length 29.9
  Bottom Layer w0.2: J18.6@34.36,65.37 36.737,65.37 38.017,66.65 55.999,66.65 58.058,68.708 58.058,70.093 59.392,71.427 R66.1@60.96,71.427
RELAY: J17.1 R36.1 | length 19.2
  Bottom Layer w0.5: R36.1@3.291,34.243 3.291,40.291 7.68,44.68 J17.1@7.68,51.6
SPI_CLK(AI): J17.5 R101.2 | length 5.6
  Bottom Layer w0.5: J17.5@17.84,51.6 17.84,53.41 18.751,54.322 R101.2@18.751,56.854
SPI_CLK(DAC): J15.13
SPI_PICO(AI): J17.4 R100.2 | length 5.9
  Bottom Layer w0.5: J17.4@15.3,51.6 15.3,53.88 16.844,55.424 R100.2@16.844,56.854
SPI_PICO(DAC): J15.14
SPI_POCI(AI): J17.7 R103.2 | length 5.4
  Bottom Layer w0.5: R103.2@22.566,56.854 22.566,54.316 22.92,53.963 J17.7@22.92,51.6
SPI_POCI(DAC): J15.15
SPI_PTE(AI): J17.6 R102.2 | length 5.4
  Bottom Layer w0.5: J17.6@20.38,51.6 20.38,53.721 20.659,54 R102.2@20.659,56.854
SPI_PTE(DAC): J15.16
Ubus: C38.1 C42.2 C59.1 D5.1 R47.2 TPDCBUS.1 U4.5 U4.8 U7.27 | length 21.1
  Bottom Layer w0.5: C42.2@33.8,28.95 33.972,29.122 34.937,29.122 35.397,29.582 35.399,29.582 38.65,32.833 38.65,34.9 41.265,37.515 42.895,37.515 D5.1@44.38,39
  Bottom Layer w1: 49.913,44.338 49.932,44.357 R47.2@49.932,49.5
VDC_AD: C56.1 J18.10 R54.1 R57.2 | length 50.6
  Top Layer w0.5: v1(28,70.209) 28,67.458 v1(29.146,66.313) ; v2(38,54) v2(41.519,54)
  Bottom Layer w0.5: v1(28,70.209) C56.1@25.952,70.209 25.952,72.267 27.61,73.925 32.754,73.925 J18.10@34.36,75.53 ; v1(29.146,66.313) 29.146,57.254 31.85,54.55 31.85,52.53 33.08,51.3 36.66,51.3 38,52.64 v2(38,54) ; v2(41.519,54) R57.2@45,54
  Bottom Layer w1: R54.1@44.985,52.073 45,52.088 R57.2@45,54
VU_AD: C73.1 J16.4 R70.1 R74.2 | length 92.1
  Top Layer w0.2: v1(22.9,78.275) 22.91,78.265 22.91,76.61 J16.4@22.92,76.6
  Bottom Layer w0.2: v1(22.9,78.275) 43.044,78.275 45.269,80.5 53.315,80.5 55.786,78.029 74.293,78.029 76.175,76.147 76.175,76.117 76.2,76.092 76.2,73.553 77.915,71.838 77.915,61.2 76.761,60.046 76.761,54.747 75.65,53.636 R70.1@75.65,51.9
  Bottom Layer w0.5: R74.2@20.166,70.178 C73.1@21.721,70.178 21.721,72.146 22.92,73.344 J16.4@22.92,76.6
VV_AD: C70.1 J16.1 R71.1 R75.2 | length 71.7
  Bottom Layer w0.2: J16.1@30.54,76.6 33.839,76.6 33.894,76.655 39.607,76.655 39.9,76.363 39.925,76.363 40.3,75.988 R75.2@40.3,75.963 C70.1@41.933,75.963 42.631,75.963 43.244,76.577 43.244,77.344 45.6,79.7 52.806,79.7 55.277,77.229 73.932,77.229 75.4,75.761 75.4,73.076 77.1,71.376 77.1,61.552 76.676,61.128 74.678,61.128 74.398,60.848 74.398,57.878 75.65,56.626 R71.1@75.65,56.351
VW_AD: C71.1 J16.5 R72.1 R76.2 | length 85.3
  Bottom Layer w0.2: J16.5@20.38,76.6 21.505,77.725 43.059,77.725 45.434,80.1 52.972,80.1 55.347,77.725 55.525,77.725 55.621,77.629 74.097,77.629 75.8,75.926 75.8,73.295 77.5,71.595 77.5,61.369 76.791,60.66 76.2,60.66 75.65,60.11 R72.1@75.65,59.835
  Bottom Layer w0.5: R76.2@16.923,70.178 C71.1@18.559,70.178 18.559,71.812 20.38,73.633 J16.5@20.38,76.6
pads on no net: D5. J15.8 J15.11 J15.12 J17.3 LBL1.0 M46.1 M46.2 M47.1 M49.1 M49.2 M50.1 M50.2 M51.1 M51.2 M52.1 M52.2 M53.1 M54.1 M55.1 M57.2 M58.2 MP1. MP2. MP3. MP4. RT1.1S RT1.2S U4.6 U6.4 U7. U7.12

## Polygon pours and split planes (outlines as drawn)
MOTOR_V on Bottom Layer "TOP_LAYER_NONET_P-001" (solid, pour order 89): 92.18,54.223 91.853,54.55 91.853,57.925 92.328,58.4 102.868,58.4 103.389,57.6 103.389,54.9 102.868,54.223
MOTOR_W on Bottom Layer "TOP_LAYER_NONET_P-001" (solid, pour order 88): 93.13,59.616 92.405,60.34 92.405,62.047 93.144,62.786 96.301,62.786 97.675,64.161 98.283,64.5 104.102,64.5 104.5,64.161 104.5,62.21 101.913,59.623
MOTOR_U on Bottom Layer "TOP_LAYER_NONET_P-001" (solid, pour order 87): 92.405,52.8 91.9,52.295 91.9,49.826 92.556,49.17 95.677,49.17 99.193,47.7 103.055,47.7 104.5,49.17 104.5,50.3 102,52.8
EGND on Bottom Layer "TOP_LAYER_NONET_P-001" (solid, pour order 86): 45.4,4.2 45.4,1.3 46.2,0.6 62.388,0.6 63.188,1.4 63.188,2.512 62.7,3 49.47,3 48.789,3.681 48.789,6.9 48.359,6.9 45.8,6.9 45.4,6.389
NEU on Bottom Layer "TOP_LAYER_NONET_P-001" (solid, pour order 20): 22.3,10.3 23.1,9.5 37.8,9.5 40,7.3 40,3.3 40.7,2.512 42.5,2.512 43,3.2 43,7.7 44.8,9.5 44.8,19.48 44.28,20 38.898,20 34.058,15.16 31.498,12.6 23.12,12.6 22.3,11.78
LINE on Bottom Layer "TOP_LAYER_NONET_P-001" (solid, pour order 51): 22,1.3 22.6,0.7 36.3,0.7 37.7,2.1 37.7,5.7 36.5,6.9 22.5,6.9 22,6.4
5V on Bottom Layer "T-G" (solid, remove dead copper, pour order 83): 23.116,61.7 23.92,60.895 24.756,60.895 24.756,64.068 24.591,64.233 20.218,64.233 19.968,63.983 19.968,62.422 19.247,61.7 19.247,59.705 19.403,59.549 21.643,59.549 21.674,59.579 21.674,60.323 21.533,60.463 20.068,60.463 19.968,60.563 19.968,61.363 20.305,61.7
5V on Bottom Layer "B-5V" (solid, remove dead copper, pour order 84): 32.5,47.309 34.844,47.309 35.399,46.754 35.399,40.395 35.108,40.103 33.037,40.103 32.5,40.64
Ubus on Bottom Layer "Bottom Layer-Ubus" (solid, pour order 16): 91.438,0.6 103.77,12.932 103.77,38.93 95,47.7 92.69,47.7 92.319,47.328 92.319,41.378 95.5,38.196 95.5,35.935 94.531,34.966 92.306,34.966 85.972,41.3 80.866,41.3 76.571,45.595 55.965,45.595 54.379,47.181 41.932,47.181 40.764,46.013 40.764,37.615 41.302,36.75 45.768,36.75 46.268,37.25 46.268,41.214 47.105,42.052 62.554,42.052 70.25,34.355 70.25,2.343 71.993,0.6
NetR8_1 on Bottom Layer "Bottom Layer-NetR8_1" (solid, pour order 80): 94.716,73.06 103.571,73.06 104.23,73.718 104.23,76.505 103.777,76.957 98.863,76.957 96.7,79.12 96.7,83.613 96.223,84.09 91.761,84.09 91.216,83.545 91.216,78.53 91.204,78.518 91.204,77.912 88.856,75.564 87.358,75.564 85.803,75.564 85.397,75.158 85.397,73.157 85.837,72.717 90.254,72.717 90.59,73.053 94.709,73.053
GND on Bottom Layer "Bottom Layer-GND" (solid, pour order 74): 85.874,78.556 86.88,77.55 89.757,77.55 90.59,78.384 90.59,84.26 90.276,84.574 86.616,84.574 85.874,83.833
NetR55_1 on Bottom Layer "Bottom Layer-NetR55_1" (solid, pour order 78): 88.002,68.059 89.581,68.059 89.581,68.068 90.478,68.068 91.035,68.624 95.103,68.624 96.473,69.994 104.004,69.994 104.004,72.307 103.594,72.717 93.7,72.717 93.7,72.723 93.694,72.717 91.684,72.717 90.724,71.757 86.357,71.757 85.96,71.36 85.96,68.523 86.423,68.059 88.002,68.059
NetC34_1 on Bottom Layer "TOP_LAYER_NONET_P-001" (solid, pour order 53): 17,18.6 19.5,21.1 26.711,21.1 31.512,25.901 36.299,25.901 41.283,30.886 44.196,30.886 45.19,29.892 45.19,23.223 43.9,21.933 38.033,21.933 30.75,14.65 17.25,14.65 17,14.9
NetK1_2 on Bottom Layer "TOP_LAYER_NONET_P-001" (solid, pour order 50): 8,0.988 8,8 6.093,9.907 6.093,17.402 7.691,19 14.268,19 15.055,18.213 15.055,15.525 18.5,12.08 18.5,1.6 17.5,0.6 8.3,0.6
NetR82_2 on Bottom Layer "TOP_LAYER_NONET_P-001" (solid, pour order 33): 90.265,66.924 91.622,68.281 94.813,68.281 95.2,67.893 95.2,64.815 94.709,64.325 91.761,64.325 91.091,63.654 87.916,63.654 87.916,66.826 88.015,66.924
NetR82_2 on Bottom Layer "TOP_LAYER_NONET_P-001" (solid, pour order 32): 89.495,63.373 86.338,63.373 85.874,63.836 85.874,66.673 86.271,67.07 89.388,67.07 89.495,66.963
GND on Bottom Layer "TOP_LAYER_NONET_P-001" (solid, pour order 29): 81.376,71.925 84.633,71.925 85.097,71.462 85.097,68.624 84.7,68.228 81.583,68.228 81.376,68.434
GND on Bottom Layer "TOP_LAYER_NONET_P-001" (solid, pour order 28): 81.376,67.297 84.533,67.297 84.997,66.834 84.997,63.997 84.6,63.6 81.483,63.6 81.376,63.707
Ubus on Bottom Layer "TOP_LAYER_NONET_P-001" (solid, pour order 17): 23.583,29.25 23.583,27.225 24.058,26.75 34.221,26.75 35.724,28.253 35.724,29.255 34.811,30.168 31.514,30.168 30.815,29.469 28.013,29.469 27.68,29.136 27.68,27.861 27.587,27.768 24.83,27.768 24.65,27.948 24.65,29.291 24.472,29.469 23.809,29.469
NetC35_2 on Bottom Layer "TOP_LAYER_NONET_P-001" (solid, pour order 13): 18.5,34.4 18.5,29.027 18.846,28.681 21.231,28.681 21.705,29.155 21.705,33.056 21.892,33.244 25.545,33.244 25.838,33.537 25.838,36.968 25.995,37.126 27.264,37.126 27.519,37.381 27.519,37.864 27.284,38.1 26.081,38.1 25.883,38.297 24.118,38.297 24.118,36.468 23.849,36.199 20.299,36.199
NetC39_2 on Bottom Layer "TOP_LAYER_NONET_P-001" (solid, pour order 6): 53.511,21.488 63.188,21.488 64.644,22.944 64.644,29.931 63.247,31.328 56.61,31.328 53.1,34.838 53.1,39.9 53.762,40.562 55.624,40.562 55.9,40.285 55.9,36.65 57.55,35 65.2,35 68.4,31.8 68.4,19.1 65.2,15.9 65.1,16 53.19,16 52.387,16.803 52.387,20.469
NetC33_1 on Bottom Layer "TOP_LAYER_NONET_P-001" (solid, pour order 5): 48.712,24 47.99,24.722 47.99,39.645 48.907,40.562 50.239,40.562 50.9,39.901 50.9,33.981 55.826,29.054 61.283,29.054 62.198,28.14 62.198,24.694 61.504,24
GND on Top Layer "Top Layer-GND 1" (solid, remove dead copper, pour order 64): 19.196,43.647 19.584,44.034 23.467,44.034 23.954,43.547 23.954,42.35 25.879,40.424 29.702,40.424 29.998,40.078 31.544,38.531 31.544,33.388 32.196,32.737 35.107,32.737 35.661,33.29 35.661,37.268 38.729,40.336 38.729,47.732 39.797,48.8 47.74,48.8 48.7,49.76 48.7,55.495 55.242,62.037 73.539,62.037 74.153,61.423 74.153,50.69 74.594,50.249 76.279,50.249 77.365,51.334 77.365,60.129 79.027,61.791 80.146,61.791 80.579,62.224 80.579,72.27 78.541,74.307 78.541,77.41 80.552,79.421 85.293,79.421 85.627,79.756 85.627,84.384 85.211,84.8 9.7,84.8 8.484,83.584 8.484,78.408 7.676,77.6 2.034,77.6 0.706,76.272 0.706,26.182 1.187,25.7 13.849,25.7 15.933,27.785 15.933,33.938 16.542,34.547 17.692,34.547 18.415,35.27 18.415,37.015 19.2,37.8 22.4,37.8 22.626,38.026 22.626,39.991 22.306,40.311 19.689,40.311 19.196,40.804
MOTOR_V on Top Layer "TOP_LAYER_NONET_P-001" (solid, pour order 26): 92.18,54.223 91.853,54.55 91.853,57.925 92.328,58.4 102.868,58.4 103.389,57.6 103.389,54.9 102.868,54.223
MOTOR_U on Top Layer "TOP_LAYER_NONET_P-001" (solid, pour order 24): 92.405,52.8 91.9,52.295 91.9,49.826 92.556,49.17 95.677,49.17 99.193,47.7 103.055,47.7 104.5,49.17 104.5,50.3 102,52.8
MOTOR_W on Top Layer "TOP_LAYER_NONET_P-001" (solid, pour order 25): 93.13,59.616 92.405,60.34 92.405,62.047 93.144,62.786 96.301,62.786 97.675,64.161 98.283,64.5 104.102,64.5 104.5,64.161 104.5,62.21 101.913,59.623
EGND on Top Layer "TOP_LAYER_NONET_P-001" (solid, pour order 54): 45.4,4.2 45.4,1.3 46.2,0.6 62.388,0.6 63.188,1.4 63.188,2.512 62.7,3 49.47,3 48.789,3.681 48.789,6.9 48.359,6.9 45.8,6.9 45.4,6.389
NEU on Top Layer "TOP_LAYER_NONET_P-001" (solid, pour order 85): 22.3,10.3 23.1,9.5 37.8,9.5 40,7.3 40,3.3 40.7,2.512 42.5,2.512 43,3.2 43,7.7 44.8,9.5 44.8,19.48 44.28,20 38.898,20 34.058,15.16 31.498,12.6 23.12,12.6 22.3,11.78
LINE on Top Layer "TOP_LAYER_NONET_P-001" (solid, pour order 19): 22,1.3 22.6,0.7 36.3,0.7 37.7,2.1 37.7,5.7 36.5,6.9 22.5,6.9 22,6.4
GND on Top Layer "Top Layer-GND" (solid, pour order 82): 57.876,38.224 58.731,37.369 64.852,37.369 70.25,31.971 70.25,2.45 72.1,0.6 91.438,0.6 103.9,13.062 103.9,29.745 94.164,39.481 92.325,41.32 92.312,41.32 89.283,44.349 89.283,76.766 89.474,76.957 90.59,78.074 90.59,84.26 90.276,84.574 86.616,84.574 85.902,83.861 85.902,79.22 85.346,78.664 85.346,74.379 83.275,72.307 81.607,72.307 81.1,71.8 81.1,50.249 81.42,49.929 83.703,49.929 85.589,48.043 85.589,43.147 84.437,41.994 80.146,41.994 77.111,45.029 59.256,45.029 57.876,43.648
NetC33_1 on Top Layer "TOP_LAYER_NONET_P-001" (solid, pour order 55): 49.913,24 47.99,25.923 47.99,39.645 48.907,40.562 50.239,40.562 50.9,39.901 50.9,33.981 55.826,29.054 61.283,29.054 62.198,28.14 62.198,24.694 61.504,24
NetR55_1 on Top Layer "Top Layer-NetR55_1" (solid, pour order 77): 89.513,68.068 90.478,68.068 91.035,68.624 95.103,68.624 96.473,69.994 104.004,69.994 104.004,72.307 103.594,72.717 93.7,72.717 93.7,72.723 93.694,72.717 91.684,72.717 90.724,71.757 89.513,71.757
